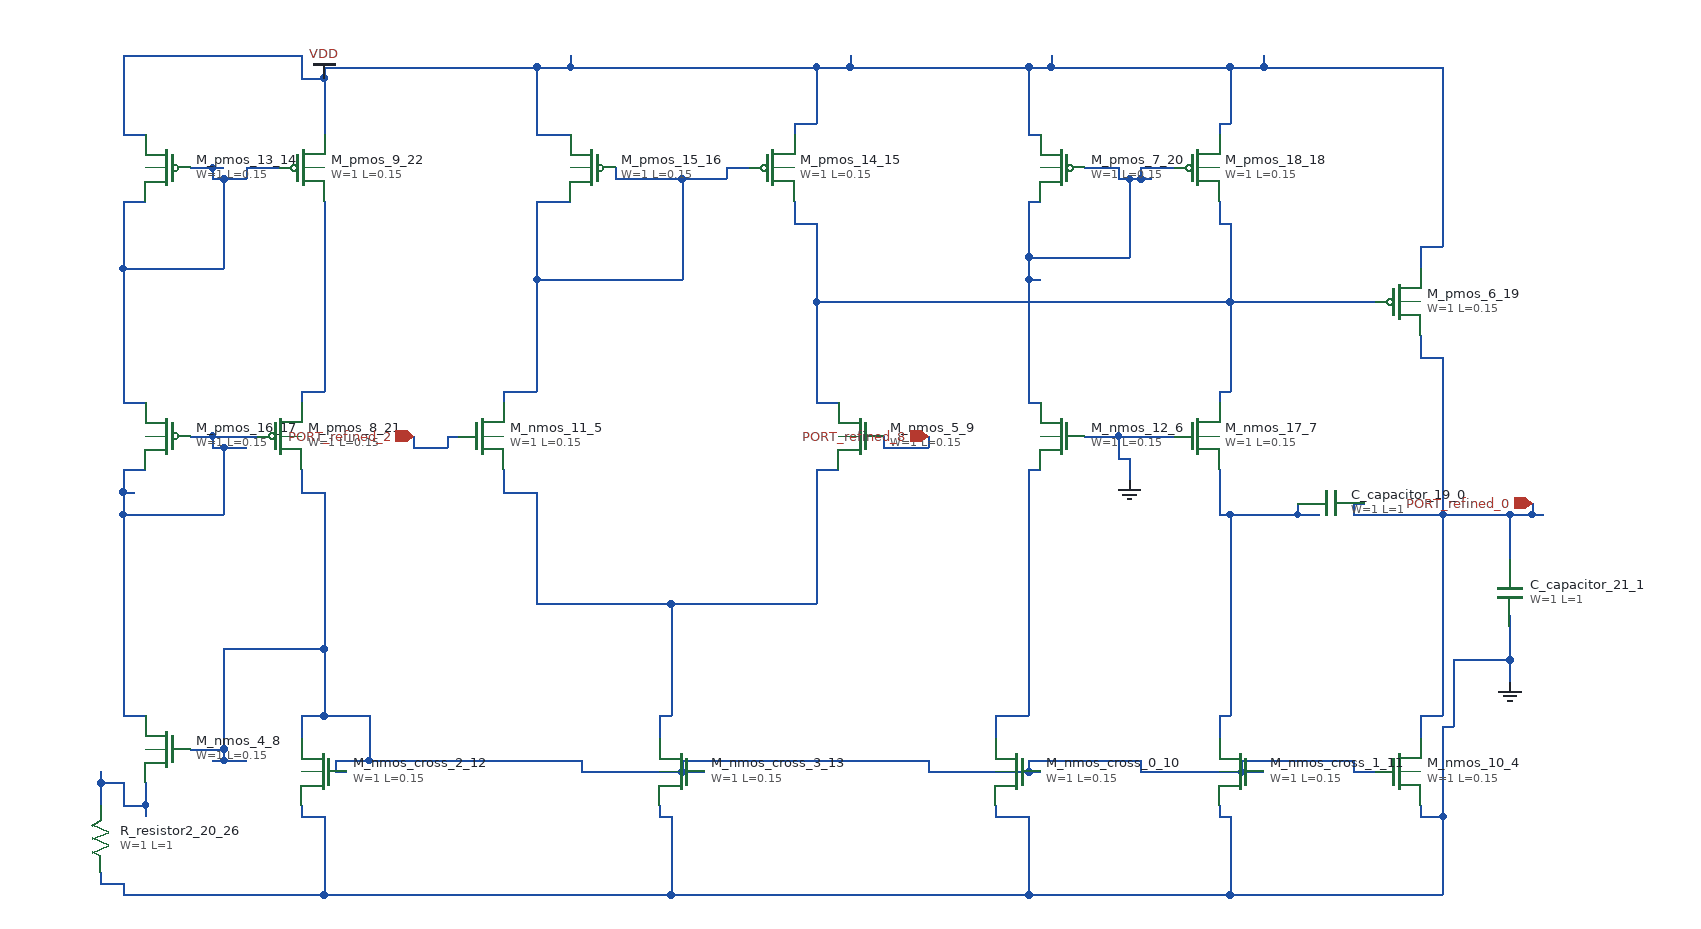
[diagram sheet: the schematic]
v {xschem version=3.4.8 file_version=1.2}
G {}
K {}
V {}
S {}
E {}
C {sky130_fd_pr/cap_mim_m3_1.sym} 1140 460 3 0 {name="C_capacitor_19_0" model=cap_mim_m3_1 W=1 L=1 MF=1 spiceprefix=X}
C {sky130_fd_pr/cap_mim_m3_1.sym} 1300 540 2 0 {name="C_capacitor_21_1" model=cap_mim_m3_1 W=1 L=1 MF=1 spiceprefix=X}
C {devices/gnd.sym} 1300 620 0 0 {name="l_gnd_22_2" lab="GND"}
C {devices/gnd.sym} 960 440 0 0 {name="l_gnd_23_3" lab="GND"}
C {sky130_fd_pr/nfet3_01v8.sym} 1200 700 0 0 {name="M_nmos_10_4"
W=1
L=0.15
body=GND
nf=1
mult=1
ad="expr('int((@nf + 1)/2) * @W / @nf * 0.29')"
pd="expr('2*int((@nf + 1)/2) * (@W / @nf + 0.29)')"
as="expr('int((@nf + 2)/2) * @W / @nf * 0.29')"
ps="expr('2*int((@nf + 2)/2) * (@W / @nf + 0.29)')"
nrd="expr('0.29 / @W ')" nrs="expr('0.29 / @W ')"
sa=0 sb=0 sd=0
model=nfet_01v8
spiceprefix=X
}
C {sky130_fd_pr/nfet3_01v8.sym} 380 400 0 0 {name="M_nmos_11_5"
W=1
L=0.15
body=GND
nf=1
mult=1
ad="expr('int((@nf + 1)/2) * @W / @nf * 0.29')"
pd="expr('2*int((@nf + 1)/2) * (@W / @nf + 0.29)')"
as="expr('int((@nf + 2)/2) * @W / @nf * 0.29')"
ps="expr('2*int((@nf + 2)/2) * (@W / @nf + 0.29)')"
nrd="expr('0.29 / @W ')" nrs="expr('0.29 / @W ')"
sa=0 sb=0 sd=0
model=nfet_01v8
spiceprefix=X
}
C {sky130_fd_pr/nfet3_01v8.sym} 900 400 0 1 {name="M_nmos_12_6"
W=1
L=0.15
body=GND
nf=1
mult=1
ad="expr('int((@nf + 1)/2) * @W / @nf * 0.29')"
pd="expr('2*int((@nf + 1)/2) * (@W / @nf + 0.29)')"
as="expr('int((@nf + 2)/2) * @W / @nf * 0.29')"
ps="expr('2*int((@nf + 2)/2) * (@W / @nf + 0.29)')"
nrd="expr('0.29 / @W ')" nrs="expr('0.29 / @W ')"
sa=0 sb=0 sd=0
model=nfet_01v8
spiceprefix=X
}
C {sky130_fd_pr/nfet3_01v8.sym} 1020 400 0 0 {name="M_nmos_17_7"
W=1
L=0.15
body=GND
nf=1
mult=1
ad="expr('int((@nf + 1)/2) * @W / @nf * 0.29')"
pd="expr('2*int((@nf + 1)/2) * (@W / @nf + 0.29)')"
as="expr('int((@nf + 2)/2) * @W / @nf * 0.29')"
ps="expr('2*int((@nf + 2)/2) * (@W / @nf + 0.29)')"
nrd="expr('0.29 / @W ')" nrs="expr('0.29 / @W ')"
sa=0 sb=0 sd=0
model=nfet_01v8
spiceprefix=X
}
C {sky130_fd_pr/nfet3_01v8.sym} 100 680 0 1 {name="M_nmos_4_8"
W=1
L=0.15
body=GND
nf=1
mult=1
ad="expr('int((@nf + 1)/2) * @W / @nf * 0.29')"
pd="expr('2*int((@nf + 1)/2) * (@W / @nf + 0.29)')"
as="expr('int((@nf + 2)/2) * @W / @nf * 0.29')"
ps="expr('2*int((@nf + 2)/2) * (@W / @nf + 0.29)')"
nrd="expr('0.29 / @W ')" nrs="expr('0.29 / @W ')"
sa=0 sb=0 sd=0
model=nfet_01v8
spiceprefix=X
}
C {sky130_fd_pr/nfet3_01v8.sym} 720 400 0 1 {name="M_nmos_5_9"
W=1
L=0.15
body=GND
nf=1
mult=1
ad="expr('int((@nf + 1)/2) * @W / @nf * 0.29')"
pd="expr('2*int((@nf + 1)/2) * (@W / @nf + 0.29)')"
as="expr('int((@nf + 2)/2) * @W / @nf * 0.29')"
ps="expr('2*int((@nf + 2)/2) * (@W / @nf + 0.29)')"
nrd="expr('0.29 / @W ')" nrs="expr('0.29 / @W ')"
sa=0 sb=0 sd=0
model=nfet_01v8
spiceprefix=X
}
C {sky130_fd_pr/nfet3_01v8.sym} 860 700 0 1 {name="M_nmos_cross_0_10"
W=1
L=0.15
body=GND
nf=1
mult=1
ad="expr('int((@nf + 1)/2) * @W / @nf * 0.29')"
pd="expr('2*int((@nf + 1)/2) * (@W / @nf + 0.29)')"
as="expr('int((@nf + 2)/2) * @W / @nf * 0.29')"
ps="expr('2*int((@nf + 2)/2) * (@W / @nf + 0.29)')"
nrd="expr('0.29 / @W ')" nrs="expr('0.29 / @W ')"
sa=0 sb=0 sd=0
model=nfet_01v8
spiceprefix=X
}
C {sky130_fd_pr/nfet3_01v8.sym} 1060 700 0 1 {name="M_nmos_cross_1_11"
W=1
L=0.15
body=GND
nf=1
mult=1
ad="expr('int((@nf + 1)/2) * @W / @nf * 0.29')"
pd="expr('2*int((@nf + 1)/2) * (@W / @nf + 0.29)')"
as="expr('int((@nf + 2)/2) * @W / @nf * 0.29')"
ps="expr('2*int((@nf + 2)/2) * (@W / @nf + 0.29)')"
nrd="expr('0.29 / @W ')" nrs="expr('0.29 / @W ')"
sa=0 sb=0 sd=0
model=nfet_01v8
spiceprefix=X
}
C {sky130_fd_pr/nfet3_01v8.sym} 240 700 0 1 {name="M_nmos_cross_2_12"
W=1
L=0.15
body=GND
nf=1
mult=1
ad="expr('int((@nf + 1)/2) * @W / @nf * 0.29')"
pd="expr('2*int((@nf + 1)/2) * (@W / @nf + 0.29)')"
as="expr('int((@nf + 2)/2) * @W / @nf * 0.29')"
ps="expr('2*int((@nf + 2)/2) * (@W / @nf + 0.29)')"
nrd="expr('0.29 / @W ')" nrs="expr('0.29 / @W ')"
sa=0 sb=0 sd=0
model=nfet_01v8
spiceprefix=X
}
C {sky130_fd_pr/nfet3_01v8.sym} 560 700 0 1 {name="M_nmos_cross_3_13"
W=1
L=0.15
body=GND
nf=1
mult=1
ad="expr('int((@nf + 1)/2) * @W / @nf * 0.29')"
pd="expr('2*int((@nf + 1)/2) * (@W / @nf + 0.29)')"
as="expr('int((@nf + 2)/2) * @W / @nf * 0.29')"
ps="expr('2*int((@nf + 2)/2) * (@W / @nf + 0.29)')"
nrd="expr('0.29 / @W ')" nrs="expr('0.29 / @W ')"
sa=0 sb=0 sd=0
model=nfet_01v8
spiceprefix=X
}
C {sky130_fd_pr/pfet3_01v8.sym} 100 160 0 1 {name="M_pmos_13_14"
W=1
L=0.15
body=VDD
nf=1
mult=1
ad="expr('int((@nf + 1)/2) * @W / @nf * 0.29')"
pd="expr('2*int((@nf + 1)/2) * (@W / @nf + 0.29)')"
as="expr('int((@nf + 2)/2) * @W / @nf * 0.29')"
ps="expr('2*int((@nf + 2)/2) * (@W / @nf + 0.29)')"
nrd="expr('0.29 / @W ')" nrs="expr('0.29 / @W ')"
sa=0 sb=0 sd=0
model=pfet_01v8
spiceprefix=X
}
C {sky130_fd_pr/pfet3_01v8.sym} 640 160 0 0 {name="M_pmos_14_15"
W=1
L=0.15
body=VDD
nf=1
mult=1
ad="expr('int((@nf + 1)/2) * @W / @nf * 0.29')"
pd="expr('2*int((@nf + 1)/2) * (@W / @nf + 0.29)')"
as="expr('int((@nf + 2)/2) * @W / @nf * 0.29')"
ps="expr('2*int((@nf + 2)/2) * (@W / @nf + 0.29)')"
nrd="expr('0.29 / @W ')" nrs="expr('0.29 / @W ')"
sa=0 sb=0 sd=0
model=pfet_01v8
spiceprefix=X
}
C {sky130_fd_pr/pfet3_01v8.sym} 480 160 0 1 {name="M_pmos_15_16"
W=1
L=0.15
body=VDD
nf=1
mult=1
ad="expr('int((@nf + 1)/2) * @W / @nf * 0.29')"
pd="expr('2*int((@nf + 1)/2) * (@W / @nf + 0.29)')"
as="expr('int((@nf + 2)/2) * @W / @nf * 0.29')"
ps="expr('2*int((@nf + 2)/2) * (@W / @nf + 0.29)')"
nrd="expr('0.29 / @W ')" nrs="expr('0.29 / @W ')"
sa=0 sb=0 sd=0
model=pfet_01v8
spiceprefix=X
}
C {sky130_fd_pr/pfet3_01v8.sym} 100 400 0 1 {name="M_pmos_16_17"
W=1
L=0.15
body=VDD
nf=1
mult=1
ad="expr('int((@nf + 1)/2) * @W / @nf * 0.29')"
pd="expr('2*int((@nf + 1)/2) * (@W / @nf + 0.29)')"
as="expr('int((@nf + 2)/2) * @W / @nf * 0.29')"
ps="expr('2*int((@nf + 2)/2) * (@W / @nf + 0.29)')"
nrd="expr('0.29 / @W ')" nrs="expr('0.29 / @W ')"
sa=0 sb=0 sd=0
model=pfet_01v8
spiceprefix=X
}
C {sky130_fd_pr/pfet3_01v8.sym} 1020 160 0 0 {name="M_pmos_18_18"
W=1
L=0.15
body=VDD
nf=1
mult=1
ad="expr('int((@nf + 1)/2) * @W / @nf * 0.29')"
pd="expr('2*int((@nf + 1)/2) * (@W / @nf + 0.29)')"
as="expr('int((@nf + 2)/2) * @W / @nf * 0.29')"
ps="expr('2*int((@nf + 2)/2) * (@W / @nf + 0.29)')"
nrd="expr('0.29 / @W ')" nrs="expr('0.29 / @W ')"
sa=0 sb=0 sd=0
model=pfet_01v8
spiceprefix=X
}
C {sky130_fd_pr/pfet3_01v8.sym} 1200 280 0 0 {name="M_pmos_6_19"
W=1
L=0.15
body=VDD
nf=1
mult=1
ad="expr('int((@nf + 1)/2) * @W / @nf * 0.29')"
pd="expr('2*int((@nf + 1)/2) * (@W / @nf + 0.29)')"
as="expr('int((@nf + 2)/2) * @W / @nf * 0.29')"
ps="expr('2*int((@nf + 2)/2) * (@W / @nf + 0.29)')"
nrd="expr('0.29 / @W ')" nrs="expr('0.29 / @W ')"
sa=0 sb=0 sd=0
model=pfet_01v8
spiceprefix=X
}
C {sky130_fd_pr/pfet3_01v8.sym} 900 160 0 1 {name="M_pmos_7_20"
W=1
L=0.15
body=VDD
nf=1
mult=1
ad="expr('int((@nf + 1)/2) * @W / @nf * 0.29')"
pd="expr('2*int((@nf + 1)/2) * (@W / @nf + 0.29)')"
as="expr('int((@nf + 2)/2) * @W / @nf * 0.29')"
ps="expr('2*int((@nf + 2)/2) * (@W / @nf + 0.29)')"
nrd="expr('0.29 / @W ')" nrs="expr('0.29 / @W ')"
sa=0 sb=0 sd=0
model=pfet_01v8
spiceprefix=X
}
C {sky130_fd_pr/pfet3_01v8.sym} 200 400 0 0 {name="M_pmos_8_21"
W=1
L=0.15
body=VDD
nf=1
mult=1
ad="expr('int((@nf + 1)/2) * @W / @nf * 0.29')"
pd="expr('2*int((@nf + 1)/2) * (@W / @nf + 0.29)')"
as="expr('int((@nf + 2)/2) * @W / @nf * 0.29')"
ps="expr('2*int((@nf + 2)/2) * (@W / @nf + 0.29)')"
nrd="expr('0.29 / @W ')" nrs="expr('0.29 / @W ')"
sa=0 sb=0 sd=0
model=pfet_01v8
spiceprefix=X
}
C {sky130_fd_pr/pfet3_01v8.sym} 220 160 0 0 {name="M_pmos_9_22"
W=1
L=0.15
body=VDD
nf=1
mult=1
ad="expr('int((@nf + 1)/2) * @W / @nf * 0.29')"
pd="expr('2*int((@nf + 1)/2) * (@W / @nf + 0.29)')"
as="expr('int((@nf + 2)/2) * @W / @nf * 0.29')"
ps="expr('2*int((@nf + 2)/2) * (@W / @nf + 0.29)')"
nrd="expr('0.29 / @W ')" nrs="expr('0.29 / @W ')"
sa=0 sb=0 sd=0
model=pfet_01v8
spiceprefix=X
}
C {devices/ipin.sym} 320 400 0 0 {name="p_port_24_23" lab="PORT_refined_2"}
C {devices/ipin.sym} 780 400 0 0 {name="p_port_25_24" lab="PORT_refined_8"}
C {devices/ipin.sym} 1320 460 0 0 {name="p_port_26_25" lab="PORT_refined_0"}
C {sky130_fd_pr/res_generic_po.sym} 40 760 2 0 {name="R_resistor2_20_26"
W=1
L=1
model=res_generic_po
spiceprefix=X
mult=1}
C {devices/vdd.sym} 240 80 0 0 {name="l_vdd_31_27" lab="VDD"}
N 1220 650 1240 650 {}
N 1160 470 1240 470 {}
N 1240 470 1300 470 {}
N 1300 470 1320 470 {}
N 1320 470 1330 470 {}
N 1160 460 1170 460 {}
N 1220 330 1240 330 {}
N 1160 470 1160 460 {}
N 1220 670 1220 650 {}
N 1220 330 1220 310 {}
N 1240 650 1240 470 {}
N 1240 470 1240 330 {}
N 1300 530 1300 510 {}
N 1300 510 1300 470 {}
N 1320 470 1320 460 {}
N 540 650 550 650 {}
N 430 550 550 550 {}
N 550 550 680 550 {}
N 400 450 430 450 {}
N 680 430 700 430 {}
N 400 450 400 430 {}
N 430 550 430 450 {}
N 540 670 540 650 {}
N 550 650 550 550 {}
N 680 550 680 430 {}
N 1220 230 1240 230 {}
N 60 130 80 130 {}
N 430 130 460 130 {}
N 870 130 880 130 {}
N 660 120 680 120 {}
N 1040 120 1050 120 {}
N 220 80 240 80 {}
N 240 70 430 70 {}
N 430 70 460 70 {}
N 460 70 680 70 {}
N 680 70 710 70 {}
N 710 70 870 70 {}
N 870 70 890 70 {}
N 890 70 1050 70 {}
N 1050 70 1080 70 {}
N 1080 70 1240 70 {}
N 60 60 220 60 {}
N 60 130 60 60 {}
N 220 80 220 60 {}
N 240 130 240 80 {}
N 240 80 240 70 {}
N 430 130 430 70 {}
N 460 70 460 60 {}
N 660 130 660 120 {}
N 680 120 680 70 {}
N 710 70 710 60 {}
N 870 130 870 70 {}
N 890 70 890 60 {}
N 1040 130 1040 120 {}
N 1050 120 1050 70 {}
N 1080 70 1080 60 {}
N 1220 250 1220 230 {}
N 1240 230 1240 70 {}
N 60 370 80 370 {}
N 60 250 150 250 {}
N 60 190 80 190 {}
N 140 170 150 170 {}
N 150 170 170 170 {}
N 120 160 140 160 {}
N 140 160 150 160 {}
N 170 160 200 160 {}
N 60 370 60 250 {}
N 60 250 60 190 {}
N 140 170 140 160 {}
N 150 250 150 170 {}
N 170 170 170 160 {}
N 400 360 430 360 {}
N 430 260 560 260 {}
N 430 190 460 190 {}
N 500 170 560 170 {}
N 560 170 600 170 {}
N 600 160 620 160 {}
N 400 370 400 360 {}
N 430 360 430 260 {}
N 430 260 430 190 {}
N 500 170 500 160 {}
N 560 260 560 170 {}
N 600 170 600 160 {}
N 60 650 80 650 {}
N 60 470 150 470 {}
N 60 450 70 450 {}
N 60 430 80 430 {}
N 140 410 150 410 {}
N 150 410 170 410 {}
N 120 400 140 400 {}
N 140 400 180 400 {}
N 60 650 60 470 {}
N 60 470 60 450 {}
N 60 450 60 430 {}
N 140 410 140 400 {}
N 150 470 150 410 {}
N 870 370 880 370 {}
N 870 260 880 260 {}
N 870 240 960 240 {}
N 870 190 880 190 {}
N 950 170 960 170 {}
N 960 170 970 170 {}
N 970 170 980 170 {}
N 920 160 950 160 {}
N 970 160 1000 160 {}
N 870 370 870 260 {}
N 870 260 870 240 {}
N 870 240 870 190 {}
N 950 170 950 160 {}
N 960 240 960 170 {}
N 970 170 970 160 {}
N 220 360 240 360 {}
N 220 370 220 360 {}
N 240 360 240 190 {}
N 320 410 350 410 {}
N 350 400 360 400 {}
N 320 410 320 400 {}
N 350 410 350 400 {}
N 840 650 870 650 {}
N 870 430 880 430 {}
N 840 670 840 650 {}
N 870 650 870 430 {}
N 680 370 700 370 {}
N 1040 360 1050 360 {}
N 680 280 1050 280 {}
N 1050 280 1180 280 {}
N 660 210 680 210 {}
N 1040 210 1050 210 {}
N 660 210 660 190 {}
N 680 370 680 280 {}
N 680 280 680 210 {}
N 1040 370 1040 360 {}
N 1040 210 1040 190 {}
N 1050 360 1050 280 {}
N 1050 280 1050 210 {}
N 1040 650 1050 650 {}
N 1040 470 1050 470 {}
N 1050 470 1110 470 {}
N 1110 470 1130 470 {}
N 1040 670 1040 650 {}
N 1040 470 1040 430 {}
N 1050 650 1050 470 {}
N 1110 470 1110 460 {}
N 60 810 240 810 {}
N 240 810 550 810 {}
N 550 810 870 810 {}
N 870 810 1050 810 {}
N 1050 810 1240 810 {}
N 40 800 60 800 {}
N 220 740 240 740 {}
N 540 740 550 740 {}
N 840 740 870 740 {}
N 1040 740 1050 740 {}
N 1220 740 1240 740 {}
N 1240 660 1250 660 {}
N 1250 600 1300 600 {}
N 950 420 960 420 {}
N 920 400 950 400 {}
N 950 400 1000 400 {}
N 40 800 40 790 {}
N 60 810 60 800 {}
N 220 740 220 730 {}
N 240 810 240 740 {}
N 540 740 540 730 {}
N 550 810 550 740 {}
N 840 740 840 730 {}
N 870 810 870 740 {}
N 950 420 950 400 {}
N 960 440 960 420 {}
N 1040 740 1040 730 {}
N 1050 810 1050 740 {}
N 1220 740 1220 730 {}
N 1240 810 1240 740 {}
N 1240 740 1240 660 {}
N 1250 660 1250 600 {}
N 1300 620 1300 600 {}
N 1300 600 1300 570 {}
N 1300 570 1300 560 {}
N 60 730 80 730 {}
N 40 710 60 710 {}
N 40 730 40 710 {}
N 40 710 40 700 {}
N 60 730 60 710 {}
N 80 740 80 730 {}
N 80 730 80 710 {}
N 740 410 780 410 {}
N 740 410 740 400 {}
N 780 410 780 400 {}
N 250 700 260 700 {}
N 470 700 560 700 {}
N 560 700 580 700 {}
N 780 700 870 700 {}
N 870 700 880 700 {}
N 970 700 1060 700 {}
N 1060 700 1080 700 {}
N 1160 700 1180 700 {}
N 140 690 150 690 {}
N 150 690 170 690 {}
N 250 690 280 690 {}
N 280 690 470 690 {}
N 560 690 780 690 {}
N 870 690 970 690 {}
N 1060 690 1160 690 {}
N 120 680 150 680 {}
N 220 650 240 650 {}
N 240 650 280 650 {}
N 150 590 240 590 {}
N 220 450 240 450 {}
N 150 690 150 680 {}
N 150 680 150 590 {}
N 220 670 220 650 {}
N 220 450 220 430 {}
N 240 650 240 590 {}
N 240 590 240 450 {}
N 250 700 250 690 {}
N 280 690 280 650 {}
N 470 700 470 690 {}
N 560 700 560 690 {}
N 780 700 780 690 {}
N 870 700 870 690 {}
N 970 700 970 690 {}
N 1060 700 1060 690 {}
N 1160 700 1160 690 {}
